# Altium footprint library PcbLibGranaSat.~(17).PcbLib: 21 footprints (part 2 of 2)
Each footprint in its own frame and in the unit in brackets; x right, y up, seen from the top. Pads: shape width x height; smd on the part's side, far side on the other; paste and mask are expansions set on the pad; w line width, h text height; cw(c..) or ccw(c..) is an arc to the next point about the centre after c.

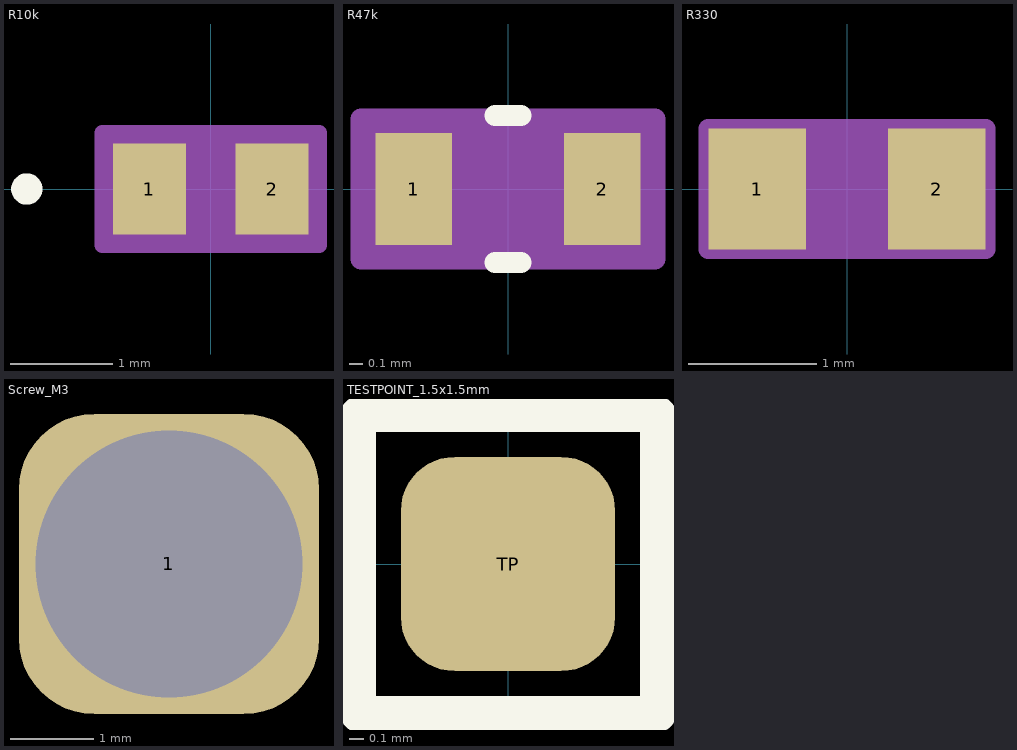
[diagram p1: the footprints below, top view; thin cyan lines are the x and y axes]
## R10k [mil]
pads (2):
  rect 28x35 smd paste+0 mask+0: 1(-23.5,0) 2(23.5,0)
Top Overlay:
  circle w6: c-70.5,0 r3
Mechanical 13:
  circle w0: c-18.5,0 r3
  lines w1: -33.5,-17.5 -33.5,17.5 ; -33.5,-17.5 33.5,-17.5 ; -33.5,-17.5 -9.5,-17.5 -9.5,17.5 -33.5,17.5 ; -33.5,-17.5 -33.5,17.5 ; -33.5,17.5 33.5,17.5 ; 33.5,-17.5 33.5,17.5 ; 33.5,-17.5 33.5,17.5 ; 33.5,-17.5 9.5,-17.5 9.5,17.5 33.5,17.5
Mechanical 15:
  region: 41.5,-21.5 -41.5,-21.5 -41.5,21.5 41.5,21.5
  lines w6: -41.5,-21.5 41.5,-21.5 41.5,21.5 -41.5,21.5 -41.5,-21.5
3D body: height 10, standoff 0, extent 0,0 10,10

## R47k [mm]
pads (2):
  rect 0.552x0.8 smd paste+0 mask+0: 1(-0.676,0) 2(0.676,0)
Top Overlay:
  lines w0.152: -0.092,-0.527 0.092,-0.527 ; -0.092,0.527 0.092,0.527
Mechanical 13:
  lines w0.025: -0.8,-0.4 -0.8,0.4 ; -0.8,-0.4 -0.4,-0.4 -0.4,0.4 -0.8,0.4 ; -0.8,-0.4 0.8,-0.4 ; -0.8,-0.4 -0.8,0.4 ; -0.8,0.4 0.8,0.4 ; 0.8,-0.4 0.4,-0.4 0.4,0.4 0.8,0.4 ; 0.8,-0.4 0.8,0.4 ; 0.8,-0.4 0.8,0.4
Mechanical 15:
  region: 1.054,-0.502 -1.054,-0.502 -1.054,0.502 1.054,0.502
  lines w0.152: -1.054,-0.502 -1.054,0.502 1.054,0.502 1.054,-0.502 -1.054,-0.502
3D body: height 0.25, standoff 0, extent 0,0 0.254,0.254

## R330 [mil]
pads (2):
  rect 30x37 smd paste+0 mask+0: 1(-27.5,0) 2(27.5,0)
Mechanical 13:
  lines w1: -32.5,-18.5 32.5,-18.5 32.5,18.5 -32.5,18.5 -32.5,-18.5
Mechanical 15:
  region: -32.5,-18.5 -42.5,-18.5 -42.5,18.5 -32.5,18.5 32.5,18.5 42.5,18.5 42.5,-18.5 32.5,-18.5
  lines w6: -42.5,-18.5 -42.5,18.5 -32.5,18.5 32.5,18.5 42.5,18.5 42.5,-18.5 32.5,-18.5 -32.5,-18.5 -42.5,-18.5
3D body: height 10, standoff 0, extent 0,0 10,10

## Screw_M3 [mm] "Main CubeSAT bus M3 screw"
pads (1):
  rrect50% 3.6x3.6 hole 3.2: 1(72.04,27.44)

## TESTPOINT_1.5x1.5mm [mm] "Punto de test de 1.5x1.5mm"
pads (1):
  rrect50% 1.5x1.5 smd: TP(0,0)
Top Overlay:
  lines w0.254: -1.05,-1.05 -1.05,1.05 1.05,1.05 1.05,-1.05 -1.05,-1.05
